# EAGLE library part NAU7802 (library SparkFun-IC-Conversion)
24-bit load cell conversion IC with I2C interface in SOIC-16 package. Similar to HX711 but with true I2C interface.

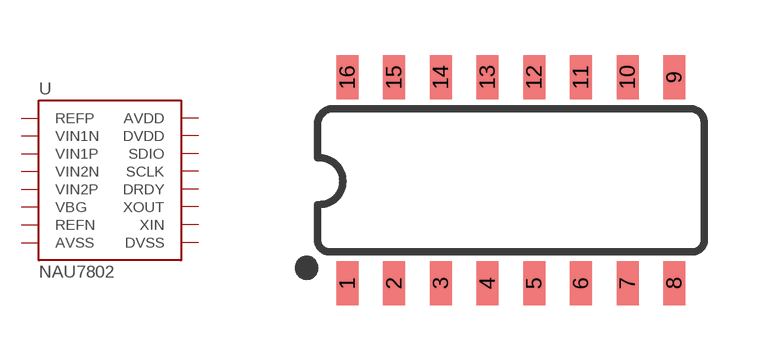
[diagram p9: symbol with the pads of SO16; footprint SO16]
Designator prefix U

## NAU7802SOIC (PROD_ID: IC-14299)  [SO16]
1  REFP
2  VIN1N
3  VIN1P
4  VIN2N
5  VIN2P
6  VBG
7  REFN
8  AVSS
9  DVSS
10  XIN
11  XOUT
12  DRDY
13  SCLK
14  SDIO
15  DVDD
16  AVDD

## Footprint SO16 (pad centres in mm)
SOIC -16 Specifications: Pin count: 16 Area: 0.15 width Example device(s): HX711
smd 0.6 x 1.2: 1 -4.445,-2.8; 2 -3.175,-2.8; 3 -1.905,-2.8; 4 -0.635,-2.8; 5 0.635,-2.8; 6 1.905,-2.8; 7 3.175,-2.8; 8 4.445,-2.8; 9 4.445,2.8; 10 3.175,2.8; 11 1.905,2.8; 12 0.635,2.8; 13 -0.635,2.8; 14 -1.905,2.8; 15 -3.175,2.8; 16 -4.445,2.8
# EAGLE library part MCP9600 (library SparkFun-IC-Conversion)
Thermocouple EMF to Temperature Converter

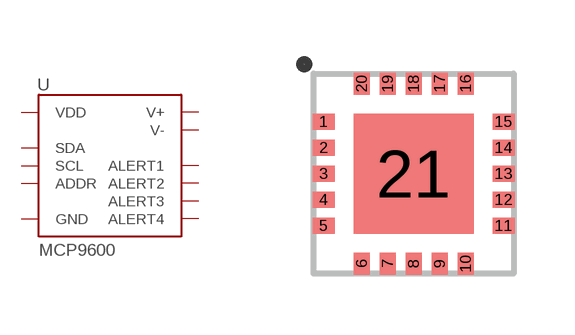
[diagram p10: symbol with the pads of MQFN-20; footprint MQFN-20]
Designator prefix U

## MCP9600-SMD (PROD_ID: IC-14644)  [MQFN-20]
1  GND
2  V+
3  GND
4  V-
5  GND
6  GND
7  GND
8  VDD
9  GND
10  GND
11  ALERT1
12  ALERT2
13  GND
14  ALERT3
15  ALERT4
16  ADDR
17  GND
18  GND
19  SCL
20  SDA
21  GND

## Footprint MQFN-20 (pad centres in mm)
smd 0.55 x 0.4: 1 -2.25,1.3; 2 -2.25,0.65; 3 -2.25,0; 4 -2.25,-0.65; 5 -2.25,-1.3; 11 2.25,-1.3; 12 2.25,-0.65; 13 2.25,0; 14 2.25,0.65; 15 2.25,1.3
smd 0.4 x 0.55: 6 -1.3,-2.25; 7 -0.65,-2.25; 8 0,-2.25; 9 0.65,-2.25; 10 1.3,-2.25; 16 1.3,2.25; 17 0.65,2.25; 18 0,2.25; 19 -0.65,2.25; 20 -1.3,2.25
smd 3 x 3: 21 0,0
